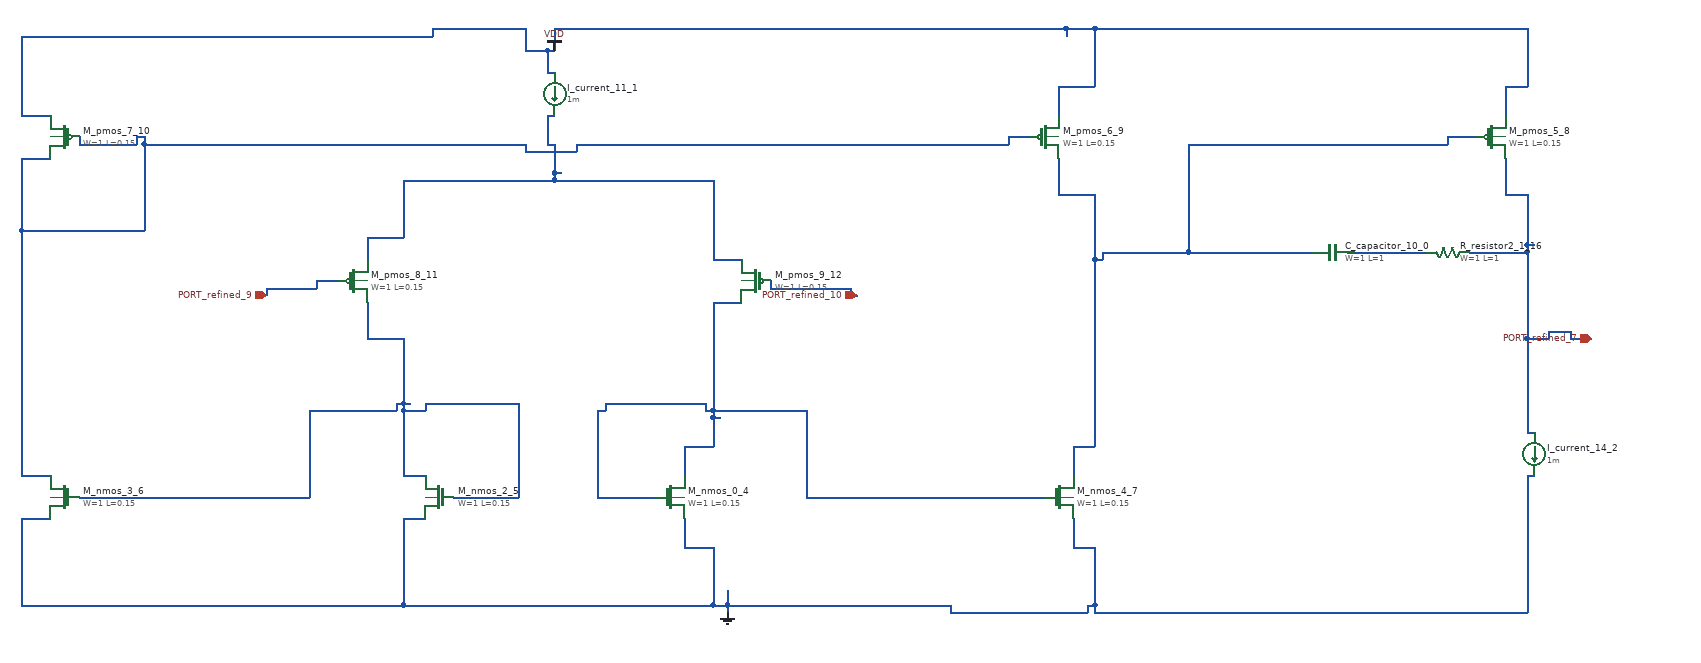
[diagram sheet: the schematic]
v {xschem version=3.4.8 file_version=1.2}
G {}
K {}
V {}
S {}
E {}
C {sky130_fd_pr/cap_mim_m3_1.sym} 1920 400 1 0 {name="C_capacitor_10_0" model=cap_mim_m3_1 W=1 L=1 MF=1 spiceprefix=X}
C {devices/isource.sym} 840 180 0 0 {name="I_current_11_1" value=1m}
C {devices/isource.sym} 2200 680 0 0 {name="I_current_14_2" value=1m}
C {devices/gnd.sym} 1080 900 0 0 {name="l_gnd_18_3" lab="GND"}
C {sky130_fd_pr/nfet3_01v8.sym} 1000 740 0 0 {name="M_nmos_0_4"
W=1
L=0.15
body=GND
nf=1
mult=1
ad="expr('int((@nf + 1)/2) * @W / @nf * 0.29')"
pd="expr('2*int((@nf + 1)/2) * (@W / @nf + 0.29)')"
as="expr('int((@nf + 2)/2) * @W / @nf * 0.29')"
ps="expr('2*int((@nf + 2)/2) * (@W / @nf + 0.29)')"
nrd="expr('0.29 / @W ')" nrs="expr('0.29 / @W ')"
sa=0 sb=0 sd=0
model=nfet_01v8
spiceprefix=X
}
C {sky130_fd_pr/nfet3_01v8.sym} 680 740 0 1 {name="M_nmos_2_5"
W=1
L=0.15
body=GND
nf=1
mult=1
ad="expr('int((@nf + 1)/2) * @W / @nf * 0.29')"
pd="expr('2*int((@nf + 1)/2) * (@W / @nf + 0.29)')"
as="expr('int((@nf + 2)/2) * @W / @nf * 0.29')"
ps="expr('2*int((@nf + 2)/2) * (@W / @nf + 0.29)')"
nrd="expr('0.29 / @W ')" nrs="expr('0.29 / @W ')"
sa=0 sb=0 sd=0
model=nfet_01v8
spiceprefix=X
}
C {sky130_fd_pr/nfet3_01v8.sym} 160 740 0 1 {name="M_nmos_3_6"
W=1
L=0.15
body=GND
nf=1
mult=1
ad="expr('int((@nf + 1)/2) * @W / @nf * 0.29')"
pd="expr('2*int((@nf + 1)/2) * (@W / @nf + 0.29)')"
as="expr('int((@nf + 2)/2) * @W / @nf * 0.29')"
ps="expr('2*int((@nf + 2)/2) * (@W / @nf + 0.29)')"
nrd="expr('0.29 / @W ')" nrs="expr('0.29 / @W ')"
sa=0 sb=0 sd=0
model=nfet_01v8
spiceprefix=X
}
C {sky130_fd_pr/nfet3_01v8.sym} 1540 740 0 0 {name="M_nmos_4_7"
W=1
L=0.15
body=GND
nf=1
mult=1
ad="expr('int((@nf + 1)/2) * @W / @nf * 0.29')"
pd="expr('2*int((@nf + 1)/2) * (@W / @nf + 0.29)')"
as="expr('int((@nf + 2)/2) * @W / @nf * 0.29')"
ps="expr('2*int((@nf + 2)/2) * (@W / @nf + 0.29)')"
nrd="expr('0.29 / @W ')" nrs="expr('0.29 / @W ')"
sa=0 sb=0 sd=0
model=nfet_01v8
spiceprefix=X
}
C {sky130_fd_pr/pfet3_01v8.sym} 2140 240 0 0 {name="M_pmos_5_8"
W=1
L=0.15
body=VDD
nf=1
mult=1
ad="expr('int((@nf + 1)/2) * @W / @nf * 0.29')"
pd="expr('2*int((@nf + 1)/2) * (@W / @nf + 0.29)')"
as="expr('int((@nf + 2)/2) * @W / @nf * 0.29')"
ps="expr('2*int((@nf + 2)/2) * (@W / @nf + 0.29)')"
nrd="expr('0.29 / @W ')" nrs="expr('0.29 / @W ')"
sa=0 sb=0 sd=0
model=pfet_01v8
spiceprefix=X
}
C {sky130_fd_pr/pfet3_01v8.sym} 1520 240 0 0 {name="M_pmos_6_9"
W=1
L=0.15
body=VDD
nf=1
mult=1
ad="expr('int((@nf + 1)/2) * @W / @nf * 0.29')"
pd="expr('2*int((@nf + 1)/2) * (@W / @nf + 0.29)')"
as="expr('int((@nf + 2)/2) * @W / @nf * 0.29')"
ps="expr('2*int((@nf + 2)/2) * (@W / @nf + 0.29)')"
nrd="expr('0.29 / @W ')" nrs="expr('0.29 / @W ')"
sa=0 sb=0 sd=0
model=pfet_01v8
spiceprefix=X
}
C {sky130_fd_pr/pfet3_01v8.sym} 160 240 0 1 {name="M_pmos_7_10"
W=1
L=0.15
body=VDD
nf=1
mult=1
ad="expr('int((@nf + 1)/2) * @W / @nf * 0.29')"
pd="expr('2*int((@nf + 1)/2) * (@W / @nf + 0.29)')"
as="expr('int((@nf + 2)/2) * @W / @nf * 0.29')"
ps="expr('2*int((@nf + 2)/2) * (@W / @nf + 0.29)')"
nrd="expr('0.29 / @W ')" nrs="expr('0.29 / @W ')"
sa=0 sb=0 sd=0
model=pfet_01v8
spiceprefix=X
}
C {sky130_fd_pr/pfet3_01v8.sym} 560 440 0 0 {name="M_pmos_8_11"
W=1
L=0.15
body=VDD
nf=1
mult=1
ad="expr('int((@nf + 1)/2) * @W / @nf * 0.29')"
pd="expr('2*int((@nf + 1)/2) * (@W / @nf + 0.29)')"
as="expr('int((@nf + 2)/2) * @W / @nf * 0.29')"
ps="expr('2*int((@nf + 2)/2) * (@W / @nf + 0.29)')"
nrd="expr('0.29 / @W ')" nrs="expr('0.29 / @W ')"
sa=0 sb=0 sd=0
model=pfet_01v8
spiceprefix=X
}
C {sky130_fd_pr/pfet3_01v8.sym} 1120 440 0 1 {name="M_pmos_9_12"
W=1
L=0.15
body=VDD
nf=1
mult=1
ad="expr('int((@nf + 1)/2) * @W / @nf * 0.29')"
pd="expr('2*int((@nf + 1)/2) * (@W / @nf + 0.29)')"
as="expr('int((@nf + 2)/2) * @W / @nf * 0.29')"
ps="expr('2*int((@nf + 2)/2) * (@W / @nf + 0.29)')"
nrd="expr('0.29 / @W ')" nrs="expr('0.29 / @W ')"
sa=0 sb=0 sd=0
model=pfet_01v8
spiceprefix=X
}
C {devices/ipin.sym} 440 460 0 0 {name="p_port_12_13" lab="PORT_refined_9"}
C {devices/ipin.sym} 1260 460 0 0 {name="p_port_13_14" lab="PORT_refined_10"}
C {devices/ipin.sym} 2280 520 0 0 {name="p_port_15_15" lab="PORT_refined_7"}
C {sky130_fd_pr/res_generic_po.sym} 2080 400 1 0 {name="R_resistor2_1_16"
W=1
L=1
model=res_generic_po
spiceprefix=X
mult=1}
C {devices/vdd.sym} 840 120 0 0 {name="l_vdd_17_17" lab="VDD"}
N 1560 670 1590 670 {}
N 1590 410 1600 410 {}
N 1600 400 1720 400 {}
N 1720 400 1890 400 {}
N 1890 400 1900 400 {}
N 1540 320 1590 320 {}
N 1720 250 2080 250 {}
N 2080 240 2120 240 {}
N 1540 320 1540 270 {}
N 1560 710 1560 670 {}
N 1590 670 1590 410 {}
N 1590 410 1590 320 {}
N 1600 410 1600 400 {}
N 1720 400 1720 250 {}
N 2080 250 2080 240 {}
N 1940 400 1950 400 {}
N 1950 400 2050 400 {}
N 1250 460 1260 460 {}
N 1140 450 1250 450 {}
N 1140 450 1140 440 {}
N 1250 460 1250 450 {}
N 180 740 500 740 {}
N 700 740 790 740 {}
N 630 710 660 710 {}
N 500 620 620 620 {}
N 630 620 660 620 {}
N 620 610 630 610 {}
N 630 610 640 610 {}
N 660 610 790 610 {}
N 580 520 630 520 {}
N 500 740 500 620 {}
N 580 520 580 470 {}
N 620 620 620 610 {}
N 630 710 630 620 {}
N 630 620 630 610 {}
N 630 610 630 520 {}
N 660 620 660 610 {}
N 790 740 790 610 {}
N 1390 900 1580 900 {}
N 1590 900 2190 900 {}
N 100 890 630 890 {}
N 630 890 1060 890 {}
N 1060 890 1080 890 {}
N 1080 890 1390 890 {}
N 1580 890 1590 890 {}
N 1020 810 1060 810 {}
N 1560 810 1590 810 {}
N 100 770 140 770 {}
N 630 770 660 770 {}
N 2190 710 2200 710 {}
N 100 890 100 770 {}
N 630 890 630 770 {}
N 1020 810 1020 770 {}
N 1060 890 1060 810 {}
N 1080 900 1080 890 {}
N 1080 890 1080 870 {}
N 1390 900 1390 890 {}
N 1560 810 1560 770 {}
N 1580 900 1580 890 {}
N 1590 900 1590 890 {}
N 1590 890 1590 810 {}
N 2190 900 2190 710 {}
N 100 710 140 710 {}
N 100 370 270 370 {}
N 100 270 140 270 {}
N 800 260 870 260 {}
N 180 250 260 250 {}
N 270 250 800 250 {}
N 870 250 1470 250 {}
N 260 240 270 240 {}
N 1470 240 1500 240 {}
N 100 710 100 370 {}
N 100 370 100 270 {}
N 180 250 180 240 {}
N 260 250 260 240 {}
N 270 370 270 250 {}
N 270 250 270 240 {}
N 800 260 800 250 {}
N 870 260 870 250 {}
N 1470 250 1470 240 {}
N 900 740 980 740 {}
N 1190 740 1520 740 {}
N 1020 670 1060 670 {}
N 1060 630 1070 630 {}
N 900 620 910 620 {}
N 1050 620 1060 620 {}
N 1060 620 1190 620 {}
N 910 610 1050 610 {}
N 1060 470 1100 470 {}
N 900 740 900 620 {}
N 910 620 910 610 {}
N 1020 710 1020 670 {}
N 1050 620 1050 610 {}
N 1060 670 1060 630 {}
N 1060 630 1060 620 {}
N 1060 620 1060 470 {}
N 1190 740 1190 620 {}
N 100 210 140 210 {}
N 1540 170 1590 170 {}
N 2160 170 2190 170 {}
N 830 150 840 150 {}
N 800 120 830 120 {}
N 830 120 840 120 {}
N 100 100 670 100 {}
N 670 90 800 90 {}
N 840 90 1550 90 {}
N 1550 90 1590 90 {}
N 1590 90 2190 90 {}
N 100 210 100 100 {}
N 670 100 670 90 {}
N 800 120 800 90 {}
N 830 150 830 120 {}
N 840 120 840 90 {}
N 1540 210 1540 170 {}
N 1550 100 1550 90 {}
N 1590 170 1590 90 {}
N 2160 210 2160 170 {}
N 2190 170 2190 90 {}
N 2190 650 2200 650 {}
N 2190 520 2220 520 {}
N 2250 520 2280 520 {}
N 2220 510 2250 510 {}
N 2110 400 2190 400 {}
N 2190 390 2200 390 {}
N 2160 320 2190 320 {}
N 2160 320 2160 270 {}
N 2190 650 2190 520 {}
N 2190 520 2190 400 {}
N 2190 400 2190 390 {}
N 2190 390 2190 320 {}
N 2220 520 2220 510 {}
N 2250 520 2250 510 {}
N 1060 410 1100 410 {}
N 580 380 630 380 {}
N 630 300 840 300 {}
N 840 300 1060 300 {}
N 840 290 850 290 {}
N 830 250 840 250 {}
N 830 210 840 210 {}
N 580 410 580 380 {}
N 630 380 630 300 {}
N 830 250 830 210 {}
N 840 300 840 290 {}
N 840 290 840 250 {}
N 1060 410 1060 300 {}
N 440 450 510 450 {}
N 510 440 540 440 {}
N 440 460 440 450 {}
N 510 450 510 440 {}
